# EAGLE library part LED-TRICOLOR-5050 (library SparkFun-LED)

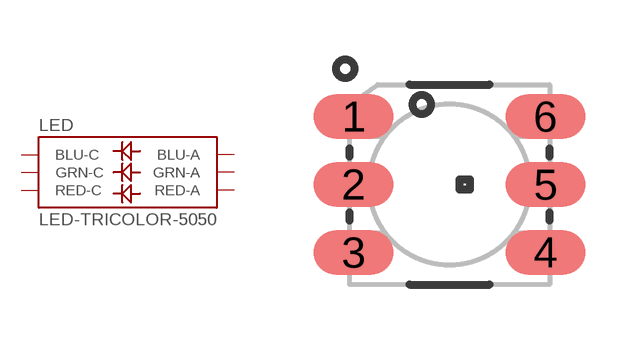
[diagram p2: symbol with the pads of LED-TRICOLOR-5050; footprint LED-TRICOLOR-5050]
Designator prefix LED

## LED-TRICOLOR-5050NO_IC (PROD_ID: DIO-10298)  [LED-TRICOLOR-5050]
1  GRN-A
2  RED-A
3  BLU-A
4  BLU-C
5  RED-C
6  GRN-C

## Footprint LED-TRICOLOR-5050 (pad centres in mm)
5050 SMD RGB LED 5.0mm x 5.0mm, 2.6mm thickness
smd 2 x 1.1: 1 -2.4,1.7; 2 -2.4,0; 3 -2.4,-1.7; 4 2.4,-1.7; 5 2.4,0; 6 2.4,1.7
